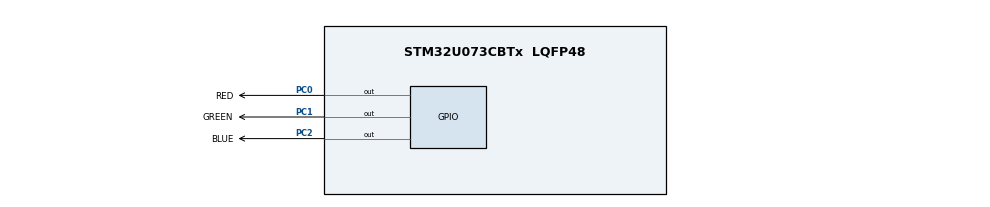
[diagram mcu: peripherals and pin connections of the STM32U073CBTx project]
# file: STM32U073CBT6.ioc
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Mcu.Family=STM32U0
Mcu.Name=STM32U073CBTx
Mcu.Package=LQFP48
NVIC.PriorityGroup=NVIC_PRIORITYGROUP_2
PA13\ (SWDIO).Mode=Serial_Wire
PA13\ (SWDIO).Signal=DEBUG_JTMS-SWDIO
PA14\ (SWCLK).Mode=Serial_Wire
PA14\ (SWCLK).Signal=DEBUG_JTCK-SWCLK
PC0.GPIO_Label=RED
PC0.GPIO_PuPd=GPIO_PULLUP
PC0.PinState=GPIO_PIN_SET
PC0.Signal=GPIO_Output
PC1.GPIO_Label=GREEN
PC1.GPIO_PuPd=GPIO_PULLUP
PC1.GPIO_Speed=GPIO_SPEED_FREQ_LOW
PC1.PinState=GPIO_PIN_SET
PC1.Signal=GPIO_Output
PC2.GPIO_Label=BLUE
PC2.GPIO_PuPd=GPIO_PULLUP
PC2.PinState=GPIO_PIN_SET
PC2.Signal=GPIO_Output
PF0-OSC_IN.Mode=HSE-External-Oscillator
PF0-OSC_IN.Signal=RCC_OSC_IN
PF1-OSC_OUT.Mode=HSE-External-Oscillator
PF1-OSC_OUT.Signal=RCC_OSC_OUT
ProjectManager.HeapSize=0x200
ProjectManager.StackSize=0x400
ProjectManager.TargetToolchain=MDK-ARM V5.39
RCC.ADCFreq_Value=56000000
RCC.AHBFreq_Value=56000000
RCC.CortexFreq_Value=56000000
RCC.HCLKFreq_Value=56000000
RCC.HSE_VALUE=8000000
RCC.HSI48_VALUE=48000000
RCC.HSI_VALUE=16000000
RCC.LSE_VALUE=32768
RCC.MSI_VALUE=4000000
RCC.PLLN=14
RCC.PLLSourceVirtual=RCC_PLLSOURCE_HSE
RCC.SYSCLKFreq_VALUE=56000000
RCC.SYSCLKSource=RCC_SYSCLKSOURCE_PLLCLK
RCC.VCOOutputFreq_Value=112000000
VP_PWR_VS_SECSignals.Mode=Security/Privilege
board=custom

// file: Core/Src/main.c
/* USER CODE BEGIN Header */
/**
  ******************************************************************************
  * @file           : main.c
  * @brief          : Main program body
  ******************************************************************************
  * @attention
  *
  * Copyright (c) 2026 STMicroelectronics.
  * All rights reserved.
  *
  * This software is licensed under terms that can be found in the LICENSE file
  * in the root directory of this software component.
  * If no LICENSE file comes with this software, it is provided AS-IS.
  *
  ******************************************************************************
  */
/* USER CODE END Header */
#include "main.h"
#include "gpio.h"

void SystemClock_Config(void);

int main(void)
{

  /* MCU Configuration--------------------------------------------------------*/

  /* Reset of all peripherals, Initializes the Flash interface and the Systick. */
  HAL_Init();

  /* Configure the system clock */
  SystemClock_Config();

  /* Initialize all configured peripherals */
  MX_GPIO_Init();

  /* Infinite loop */
  /* USER CODE BEGIN WHILE */
  while (1)
  {
		HAL_GPIO_TogglePin(LED_GPIO_Port, LED_Pin);
		HAL_Delay(500);
    /* USER CODE END WHILE */

  }
}

void SystemClock_Config(void)
{
  RCC_OscInitTypeDef RCC_OscInitStruct = {0};
  RCC_ClkInitTypeDef RCC_ClkInitStruct = {0};

  /** Configure the main internal regulator output voltage
  */
  HAL_PWREx_ControlVoltageScaling(PWR_REGULATOR_VOLTAGE_SCALE1);

  /** Initializes the RCC Oscillators according to the specified parameters
  * in the RCC_OscInitTypeDef structure.
  */
  RCC_OscInitStruct.OscillatorType = RCC_OSCILLATORTYPE_MSI;
  RCC_OscInitStruct.MSIState = RCC_MSI_ON;
  RCC_OscInitStruct.MSICalibrationValue = RCC_MSICALIBRATION_DEFAULT;
  RCC_OscInitStruct.MSIClockRange = RCC_MSIRANGE_11;
  RCC_OscInitStruct.PLL.PLLState = RCC_PLL_NONE;
  if (HAL_RCC_OscConfig(&RCC_OscInitStruct) != HAL_OK)
  {
    Error_Handler();
  }

  /** Initializes the CPU, AHB and APB buses clocks
  */
  RCC_ClkInitStruct.ClockType = RCC_CLOCKTYPE_HCLK|RCC_CLOCKTYPE_SYSCLK
                              |RCC_CLOCKTYPE_PCLK1;
  RCC_ClkInitStruct.SYSCLKSource = RCC_SYSCLKSOURCE_MSI;
  RCC_ClkInitStruct.AHBCLKDivider = RCC_SYSCLK_DIV1;
  RCC_ClkInitStruct.APB1CLKDivider = RCC_HCLK_DIV1;

  if (HAL_RCC_ClockConfig(&RCC_ClkInitStruct, FLASH_LATENCY_1) != HAL_OK)
  {
    Error_Handler();
  }
}

void Error_Handler(void)
{
  __disable_irq();
  while (1)
  {
  }
}
